VERSION 5.7 ;
  NOWIREEXTENSIONATPIN ON ;
  DIVIDERCHAR "/" ;
  BUSBITCHARS "[]" ;
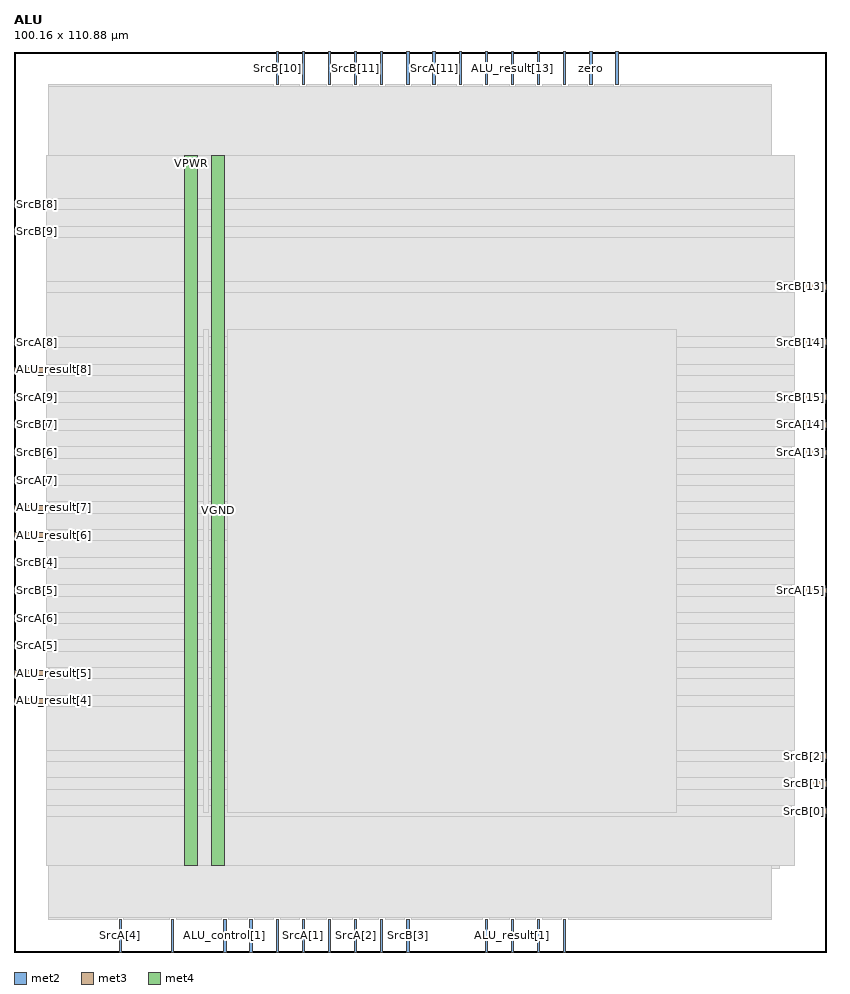
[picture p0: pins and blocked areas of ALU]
MACRO ALU
  CLASS BLOCK ;
  FOREIGN ALU ;
  ORIGIN 0.000 0.000 ;
  SIZE 100.160 BY 110.880 ;
  PIN ALU_control[0]
    DIRECTION INPUT ;
    USE SIGNAL ;
    ANTENNAGATEAREA 0.196500 ;
    PORT
      LAYER met2 ;
        RECT 19.410 0.000 19.690 4.000 ;
    END
  END ALU_control[0]
  PIN ALU_control[1]
    DIRECTION INPUT ;
    USE SIGNAL ;
    ANTENNAGATEAREA 0.196500 ;
    PORT
      LAYER met2 ;
        RECT 25.850 0.000 26.130 4.000 ;
    END
  END ALU_control[1]
  PIN ALU_control[2]
    DIRECTION INPUT ;
    USE SIGNAL ;
    ANTENNAGATEAREA 0.213000 ;
    PORT
      LAYER met2 ;
        RECT 29.070 0.000 29.350 4.000 ;
    END
  END ALU_control[2]
  PIN ALU_control[3]
    DIRECTION INPUT ;
    USE SIGNAL ;
    ANTENNAGATEAREA 0.213000 ;
    PORT
      LAYER met2 ;
        RECT 32.290 0.000 32.570 4.000 ;
    END
  END ALU_control[3]
  PIN ALU_result[0]
    DIRECTION OUTPUT ;
    USE SIGNAL ;
    ANTENNADIFFAREA 0.445500 ;
    PORT
      LAYER met2 ;
        RECT 64.490 0.000 64.770 4.000 ;
    END
  END ALU_result[0]
  PIN ALU_result[10]
    DIRECTION OUTPUT ;
    USE SIGNAL ;
    ANTENNADIFFAREA 0.445500 ;
    PORT
      LAYER met2 ;
        RECT 48.390 106.880 48.670 110.880 ;
    END
  END ALU_result[10]
  PIN ALU_result[11]
    DIRECTION OUTPUT ;
    USE SIGNAL ;
    ANTENNADIFFAREA 0.445500 ;
    PORT
      LAYER met2 ;
        RECT 45.170 106.880 45.450 110.880 ;
    END
  END ALU_result[11]
  PIN ALU_result[12]
    DIRECTION OUTPUT ;
    USE SIGNAL ;
    ANTENNADIFFAREA 0.445500 ;
    PORT
      LAYER met2 ;
        RECT 54.830 106.880 55.110 110.880 ;
    END
  END ALU_result[12]
  PIN ALU_result[13]
    DIRECTION OUTPUT ;
    USE SIGNAL ;
    ANTENNADIFFAREA 0.445500 ;
    PORT
      LAYER met2 ;
        RECT 61.270 106.880 61.550 110.880 ;
    END
  END ALU_result[13]
  PIN ALU_result[14]
    DIRECTION OUTPUT ;
    USE SIGNAL ;
    ANTENNADIFFAREA 0.445500 ;
    PORT
      LAYER met2 ;
        RECT 67.710 106.880 67.990 110.880 ;
    END
  END ALU_result[14]
  PIN ALU_result[15]
    DIRECTION OUTPUT ;
    USE SIGNAL ;
    ANTENNADIFFAREA 0.445500 ;
    PORT
      LAYER met2 ;
        RECT 74.150 106.880 74.430 110.880 ;
    END
  END ALU_result[15]
  PIN ALU_result[1]
    DIRECTION OUTPUT ;
    USE SIGNAL ;
    ANTENNADIFFAREA 0.445500 ;
    PORT
      LAYER met2 ;
        RECT 61.270 0.000 61.550 4.000 ;
    END
  END ALU_result[1]
  PIN ALU_result[2]
    DIRECTION OUTPUT ;
    USE SIGNAL ;
    ANTENNADIFFAREA 0.445500 ;
    PORT
      LAYER met2 ;
        RECT 67.710 0.000 67.990 4.000 ;
    END
  END ALU_result[2]
  PIN ALU_result[3]
    DIRECTION OUTPUT ;
    USE SIGNAL ;
    ANTENNADIFFAREA 0.445500 ;
    PORT
      LAYER met2 ;
        RECT 58.050 0.000 58.330 4.000 ;
    END
  END ALU_result[3]
  PIN ALU_result[4]
    DIRECTION OUTPUT ;
    USE SIGNAL ;
    ANTENNADIFFAREA 0.445500 ;
    PORT
      LAYER met3 ;
        RECT 0.000 30.640 4.000 31.240 ;
    END
  END ALU_result[4]
  PIN ALU_result[5]
    DIRECTION OUTPUT ;
    USE SIGNAL ;
    ANTENNADIFFAREA 0.445500 ;
    PORT
      LAYER met3 ;
        RECT 0.000 34.040 4.000 34.640 ;
    END
  END ALU_result[5]
  PIN ALU_result[6]
    DIRECTION OUTPUT ;
    USE SIGNAL ;
    ANTENNADIFFAREA 0.445500 ;
    PORT
      LAYER met3 ;
        RECT 0.000 51.040 4.000 51.640 ;
    END
  END ALU_result[6]
  PIN ALU_result[7]
    DIRECTION OUTPUT ;
    USE SIGNAL ;
    ANTENNADIFFAREA 0.445500 ;
    PORT
      LAYER met3 ;
        RECT 0.000 54.440 4.000 55.040 ;
    END
  END ALU_result[7]
  PIN ALU_result[8]
    DIRECTION OUTPUT ;
    USE SIGNAL ;
    ANTENNADIFFAREA 0.445500 ;
    PORT
      LAYER met3 ;
        RECT 0.000 71.440 4.000 72.040 ;
    END
  END ALU_result[8]
  PIN ALU_result[9]
    DIRECTION OUTPUT ;
    USE SIGNAL ;
    ANTENNADIFFAREA 0.445500 ;
    PORT
      LAYER met2 ;
        RECT 35.510 106.880 35.790 110.880 ;
    END
  END ALU_result[9]
  PIN SrcA[0]
    DIRECTION INPUT ;
    USE SIGNAL ;
    ANTENNAGATEAREA 0.159000 ;
    PORT
      LAYER met2 ;
        RECT 38.730 0.000 39.010 4.000 ;
    END
  END SrcA[0]
  PIN SrcA[10]
    DIRECTION INPUT ;
    USE SIGNAL ;
    ANTENNAGATEAREA 0.196500 ;
    PORT
      LAYER met2 ;
        RECT 38.730 106.880 39.010 110.880 ;
    END
  END SrcA[10]
  PIN SrcA[11]
    DIRECTION INPUT ;
    USE SIGNAL ;
    ANTENNAGATEAREA 0.196500 ;
    PORT
      LAYER met2 ;
        RECT 51.610 106.880 51.890 110.880 ;
    END
  END SrcA[11]
  PIN SrcA[12]
    DIRECTION INPUT ;
    USE SIGNAL ;
    ANTENNAGATEAREA 0.196500 ;
    PORT
      LAYER met2 ;
        RECT 64.490 106.880 64.770 110.880 ;
    END
  END SrcA[12]
  PIN SrcA[13]
    DIRECTION INPUT ;
    USE SIGNAL ;
    ANTENNAGATEAREA 0.196500 ;
    PORT
      LAYER met3 ;
        RECT 96.160 61.240 100.160 61.840 ;
    END
  END SrcA[13]
  PIN SrcA[14]
    DIRECTION INPUT ;
    USE SIGNAL ;
    ANTENNAGATEAREA 0.196500 ;
    PORT
      LAYER met3 ;
        RECT 96.160 64.640 100.160 65.240 ;
    END
  END SrcA[14]
  PIN SrcA[15]
    DIRECTION INPUT ;
    USE SIGNAL ;
    ANTENNAGATEAREA 0.196500 ;
    PORT
      LAYER met3 ;
        RECT 96.160 44.240 100.160 44.840 ;
    END
  END SrcA[15]
  PIN SrcA[1]
    DIRECTION INPUT ;
    USE SIGNAL ;
    ANTENNAGATEAREA 0.196500 ;
    PORT
      LAYER met2 ;
        RECT 35.510 0.000 35.790 4.000 ;
    END
  END SrcA[1]
  PIN SrcA[2]
    DIRECTION INPUT ;
    USE SIGNAL ;
    ANTENNAGATEAREA 0.196500 ;
    PORT
      LAYER met2 ;
        RECT 41.950 0.000 42.230 4.000 ;
    END
  END SrcA[2]
  PIN SrcA[3]
    DIRECTION INPUT ;
    USE SIGNAL ;
    ANTENNAGATEAREA 0.196500 ;
    PORT
      LAYER met2 ;
        RECT 45.170 0.000 45.450 4.000 ;
    END
  END SrcA[3]
  PIN SrcA[4]
    DIRECTION INPUT ;
    USE SIGNAL ;
    ANTENNAGATEAREA 0.196500 ;
    PORT
      LAYER met2 ;
        RECT 12.970 0.000 13.250 4.000 ;
    END
  END SrcA[4]
  PIN SrcA[5]
    DIRECTION INPUT ;
    USE SIGNAL ;
    ANTENNAGATEAREA 0.196500 ;
    PORT
      LAYER met3 ;
        RECT 0.000 37.440 4.000 38.040 ;
    END
  END SrcA[5]
  PIN SrcA[6]
    DIRECTION INPUT ;
    USE SIGNAL ;
    ANTENNAGATEAREA 0.196500 ;
    PORT
      LAYER met3 ;
        RECT 0.000 40.840 4.000 41.440 ;
    END
  END SrcA[6]
  PIN SrcA[7]
    DIRECTION INPUT ;
    USE SIGNAL ;
    ANTENNAGATEAREA 0.196500 ;
    PORT
      LAYER met3 ;
        RECT 0.000 57.840 4.000 58.440 ;
    END
  END SrcA[7]
  PIN SrcA[8]
    DIRECTION INPUT ;
    USE SIGNAL ;
    ANTENNAGATEAREA 0.196500 ;
    PORT
      LAYER met3 ;
        RECT 0.000 74.840 4.000 75.440 ;
    END
  END SrcA[8]
  PIN SrcA[9]
    DIRECTION INPUT ;
    USE SIGNAL ;
    ANTENNAGATEAREA 0.196500 ;
    PORT
      LAYER met3 ;
        RECT 0.000 68.040 4.000 68.640 ;
    END
  END SrcA[9]
  PIN SrcB[0]
    DIRECTION INPUT ;
    USE SIGNAL ;
    ANTENNAGATEAREA 0.196500 ;
    PORT
      LAYER met3 ;
        RECT 96.160 17.040 100.160 17.640 ;
    END
  END SrcB[0]
  PIN SrcB[10]
    DIRECTION INPUT ;
    USE SIGNAL ;
    ANTENNAGATEAREA 0.126000 ;
    PORT
      LAYER met2 ;
        RECT 32.290 106.880 32.570 110.880 ;
    END
  END SrcB[10]
  PIN SrcB[11]
    DIRECTION INPUT ;
    USE SIGNAL ;
    ANTENNAGATEAREA 0.126000 ;
    PORT
      LAYER met2 ;
        RECT 41.950 106.880 42.230 110.880 ;
    END
  END SrcB[11]
  PIN SrcB[12]
    DIRECTION INPUT ;
    USE SIGNAL ;
    ANTENNAGATEAREA 0.126000 ;
    PORT
      LAYER met2 ;
        RECT 58.050 106.880 58.330 110.880 ;
    END
  END SrcB[12]
  PIN SrcB[13]
    DIRECTION INPUT ;
    USE SIGNAL ;
    ANTENNAGATEAREA 0.126000 ;
    PORT
      LAYER met3 ;
        RECT 96.160 81.640 100.160 82.240 ;
    END
  END SrcB[13]
  PIN SrcB[14]
    DIRECTION INPUT ;
    USE SIGNAL ;
    ANTENNAGATEAREA 0.126000 ;
    PORT
      LAYER met3 ;
        RECT 96.160 74.840 100.160 75.440 ;
    END
  END SrcB[14]
  PIN SrcB[15]
    DIRECTION INPUT ;
    USE SIGNAL ;
    ANTENNAGATEAREA 0.196500 ;
    PORT
      LAYER met3 ;
        RECT 96.160 68.040 100.160 68.640 ;
    END
  END SrcB[15]
  PIN SrcB[1]
    DIRECTION INPUT ;
    USE SIGNAL ;
    ANTENNAGATEAREA 0.196500 ;
    PORT
      LAYER met3 ;
        RECT 96.160 20.440 100.160 21.040 ;
    END
  END SrcB[1]
  PIN SrcB[2]
    DIRECTION INPUT ;
    USE SIGNAL ;
    ANTENNAGATEAREA 0.196500 ;
    PORT
      LAYER met3 ;
        RECT 96.160 23.840 100.160 24.440 ;
    END
  END SrcB[2]
  PIN SrcB[3]
    DIRECTION INPUT ;
    USE SIGNAL ;
    ANTENNAGATEAREA 0.196500 ;
    PORT
      LAYER met2 ;
        RECT 48.390 0.000 48.670 4.000 ;
    END
  END SrcB[3]
  PIN SrcB[4]
    DIRECTION INPUT ;
    USE SIGNAL ;
    ANTENNAGATEAREA 0.213000 ;
    PORT
      LAYER met3 ;
        RECT 0.000 47.640 4.000 48.240 ;
    END
  END SrcB[4]
  PIN SrcB[5]
    DIRECTION INPUT ;
    USE SIGNAL ;
    ANTENNAGATEAREA 0.213000 ;
    PORT
      LAYER met3 ;
        RECT 0.000 44.240 4.000 44.840 ;
    END
  END SrcB[5]
  PIN SrcB[6]
    DIRECTION INPUT ;
    USE SIGNAL ;
    ANTENNAGATEAREA 0.196500 ;
    PORT
      LAYER met3 ;
        RECT 0.000 61.240 4.000 61.840 ;
    END
  END SrcB[6]
  PIN SrcB[7]
    DIRECTION INPUT ;
    USE SIGNAL ;
    ANTENNAGATEAREA 0.126000 ;
    PORT
      LAYER met3 ;
        RECT 0.000 64.640 4.000 65.240 ;
    END
  END SrcB[7]
  PIN SrcB[8]
    DIRECTION INPUT ;
    USE SIGNAL ;
    ANTENNAGATEAREA 0.213000 ;
    PORT
      LAYER met3 ;
        RECT 0.000 91.840 4.000 92.440 ;
    END
  END SrcB[8]
  PIN SrcB[9]
    DIRECTION INPUT ;
    USE SIGNAL ;
    ANTENNAGATEAREA 0.213000 ;
    PORT
      LAYER met3 ;
        RECT 0.000 88.440 4.000 89.040 ;
    END
  END SrcB[9]
  PIN VGND
    DIRECTION INOUT ;
    USE GROUND ;
    PORT
      LAYER met4 ;
        RECT 24.340 10.640 25.940 98.160 ;
    END
  END VGND
  PIN VPWR
    DIRECTION INOUT ;
    USE POWER ;
    PORT
      LAYER met4 ;
        RECT 21.040 10.640 22.640 98.160 ;
    END
  END VPWR
  PIN zero
    DIRECTION OUTPUT ;
    USE SIGNAL ;
    ANTENNADIFFAREA 0.445500 ;
    PORT
      LAYER met2 ;
        RECT 70.930 106.880 71.210 110.880 ;
    END
  END zero
  OBS
      LAYER nwell ;
        RECT 5.330 10.795 94.490 98.005 ;
      LAYER li1 ;
        RECT 5.520 10.795 94.300 98.005 ;
      LAYER met1 ;
        RECT 4.210 10.240 94.300 98.160 ;
      LAYER met2 ;
        RECT 4.230 106.600 32.010 106.880 ;
        RECT 32.850 106.600 35.230 106.880 ;
        RECT 36.070 106.600 38.450 106.880 ;
        RECT 39.290 106.600 41.670 106.880 ;
        RECT 42.510 106.600 44.890 106.880 ;
        RECT 45.730 106.600 48.110 106.880 ;
        RECT 48.950 106.600 51.330 106.880 ;
        RECT 52.170 106.600 54.550 106.880 ;
        RECT 55.390 106.600 57.770 106.880 ;
        RECT 58.610 106.600 60.990 106.880 ;
        RECT 61.830 106.600 64.210 106.880 ;
        RECT 65.050 106.600 67.430 106.880 ;
        RECT 68.270 106.600 70.650 106.880 ;
        RECT 71.490 106.600 73.870 106.880 ;
        RECT 74.710 106.600 93.280 106.880 ;
        RECT 4.230 4.280 93.280 106.600 ;
        RECT 4.230 4.000 12.690 4.280 ;
        RECT 13.530 4.000 19.130 4.280 ;
        RECT 19.970 4.000 25.570 4.280 ;
        RECT 26.410 4.000 28.790 4.280 ;
        RECT 29.630 4.000 32.010 4.280 ;
        RECT 32.850 4.000 35.230 4.280 ;
        RECT 36.070 4.000 38.450 4.280 ;
        RECT 39.290 4.000 41.670 4.280 ;
        RECT 42.510 4.000 44.890 4.280 ;
        RECT 45.730 4.000 48.110 4.280 ;
        RECT 48.950 4.000 57.770 4.280 ;
        RECT 58.610 4.000 60.990 4.280 ;
        RECT 61.830 4.000 64.210 4.280 ;
        RECT 65.050 4.000 67.430 4.280 ;
        RECT 68.270 4.000 93.280 4.280 ;
      LAYER met3 ;
        RECT 3.990 92.840 96.160 98.085 ;
        RECT 4.400 91.440 96.160 92.840 ;
        RECT 3.990 89.440 96.160 91.440 ;
        RECT 4.400 88.040 96.160 89.440 ;
        RECT 3.990 82.640 96.160 88.040 ;
        RECT 3.990 81.240 95.760 82.640 ;
        RECT 3.990 75.840 96.160 81.240 ;
        RECT 4.400 74.440 95.760 75.840 ;
        RECT 3.990 72.440 96.160 74.440 ;
        RECT 4.400 71.040 96.160 72.440 ;
        RECT 3.990 69.040 96.160 71.040 ;
        RECT 4.400 67.640 95.760 69.040 ;
        RECT 3.990 65.640 96.160 67.640 ;
        RECT 4.400 64.240 95.760 65.640 ;
        RECT 3.990 62.240 96.160 64.240 ;
        RECT 4.400 60.840 95.760 62.240 ;
        RECT 3.990 58.840 96.160 60.840 ;
        RECT 4.400 57.440 96.160 58.840 ;
        RECT 3.990 55.440 96.160 57.440 ;
        RECT 4.400 54.040 96.160 55.440 ;
        RECT 3.990 52.040 96.160 54.040 ;
        RECT 4.400 50.640 96.160 52.040 ;
        RECT 3.990 48.640 96.160 50.640 ;
        RECT 4.400 47.240 96.160 48.640 ;
        RECT 3.990 45.240 96.160 47.240 ;
        RECT 4.400 43.840 95.760 45.240 ;
        RECT 3.990 41.840 96.160 43.840 ;
        RECT 4.400 40.440 96.160 41.840 ;
        RECT 3.990 38.440 96.160 40.440 ;
        RECT 4.400 37.040 96.160 38.440 ;
        RECT 3.990 35.040 96.160 37.040 ;
        RECT 4.400 33.640 96.160 35.040 ;
        RECT 3.990 31.640 96.160 33.640 ;
        RECT 4.400 30.240 96.160 31.640 ;
        RECT 3.990 24.840 96.160 30.240 ;
        RECT 3.990 23.440 95.760 24.840 ;
        RECT 3.990 21.440 96.160 23.440 ;
        RECT 3.990 20.040 95.760 21.440 ;
        RECT 3.990 18.040 96.160 20.040 ;
        RECT 3.990 16.640 95.760 18.040 ;
        RECT 3.990 10.715 96.160 16.640 ;
      LAYER met4 ;
        RECT 23.295 17.175 23.940 76.665 ;
        RECT 26.340 17.175 81.585 76.665 ;
  END
END ALU
END LIBRARY

